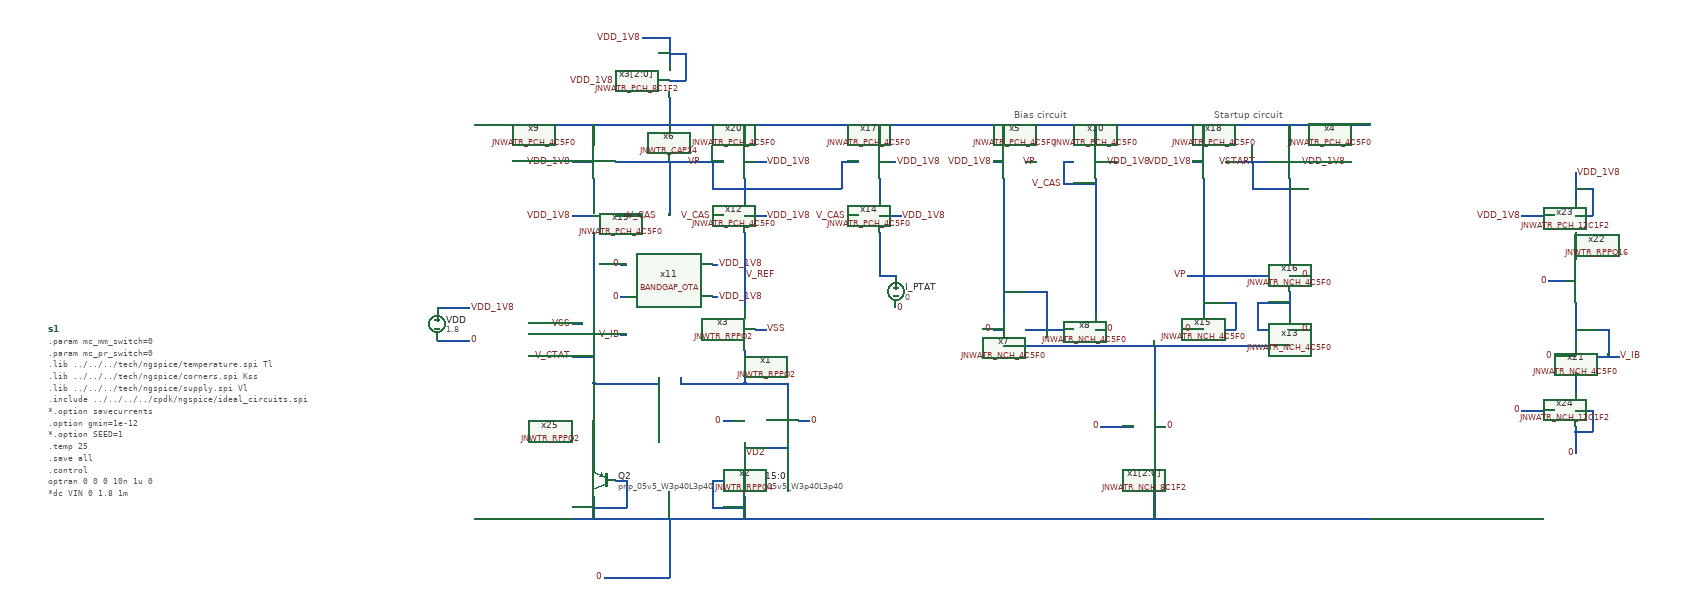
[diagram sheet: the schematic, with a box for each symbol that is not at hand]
v {xschem version=3.4.7 file_version=1.2}
G {}
K {}
V {}
S {}
E {}
B 2 -1480 -430 -680 -30 {flags=graph
y1=-2.0070292e-10
y2=1.6056831e-10
ypos1=0
ypos2=2
divy=5
subdivy=1
unity=1
x1=-0.00047041005
x2=0.0022870997
divx=5
subdivx=1
xlabmag=1.0
ylabmag=1.0
dataset=-1
unitx=1
logx=0
logy=0
hilight_wave=0
color=4
node=i(vdd)}
T {Startup circuit} 970 -230 0 0 0.4 0.4 {}
T {Bias circuit} 600 -230 0 0 0.4 0.4 {}
N -140 -130 60 -130 {lab=VP}
N -60 270 -60 280 {lab=V_CTAT}
N -180 280 -60 280 {lab=V_CTAT}
N -20 270 -20 280 {lab=DV}
N 100 390 100 430 {lab=VD2}
N -180 280 -180 430 {lab=V_CTAT}
N 40 510 100 510 {lab=0}
N 40 460 40 510 {lab=0}
N 40 460 60 460 {lab=0}
N 350 -130 380 -130 {lab=VDD_1V8}
N 280 -130 310 -130 {lab=VP}
N 350 0 350 80 {lab=#net1}
N -130 120 -120 120 {lab=0}
N 40 120 50 120 {lab=VDD_1V8}
N 100 -130 140 -130 {lab=VDD_1V8}
N -220 -130 -180 -130 {lab=VDD_1V8}
N -180 -200 -180 -160 {lab=#net2}
N 100 -200 100 -160 {lab=#net2}
N 350 -200 350 -160 {lab=#net2}
N 350 80 380 80 {lab=#net1}
N -220 230 -180 230 {lab=V_CTAT}
N 40 -130 40 -80 {lab=VP}
N 280 -130 280 -80 {lab=VP}
N -40 -130 -40 -30 {lab=VP}
N -40 -250 -40 -200 {lab=#net2}
N -140 -280 -80 -280 {lab=VDD_1V8}
N -40 -360 -40 -310 {lab=VDD_1V8}
N -90 -360 -40 -360 {lab=VDD_1V8}
N 40 60 50 60 {lab=VDD_1V8}
N -40 -280 -10 -280 {lab=VDD_1V8}
N -10 -330 -10 -280 {lab=VDD_1V8}
N -40 -330 -10 -330 {lab=VDD_1V8}
N -130 60 -120 60 {lab=0}
N -130 190 -120 190 {lab=V_IB}
N 580 -80 580 -60 {lab=#net3}
N 580 -100 580 -80 {lab=#net3}
N 580 -200 580 -160 {lab=#net2}
N -220 -30 -180 -30 {lab=VDD_1V8}
N -140 -30 -120 -30 {lab=V_CAS}
N -180 -100 -180 -60 {lab=#net4}
N 100 -100 100 -60 {lab=#net5}
N 100 -30 140 -30 {lab=VDD_1V8}
N 40 -30 60 -30 {lab=V_CAS}
N 350 -30 390 -30 {lab=VDD_1V8}
N 350 -100 350 -60 {lab=#net6}
N 290 -30 310 -30 {lab=V_CAS}
N 580 -60 580 -10 {lab=#net3}
N 580 -10 580 150 {lab=#net3}
N -180 510 -120 510 {lab=0}
N -120 460 -120 510 {lab=0}
N -140 460 -120 460 {lab=0}
N 620 180 640 180 {lab=#net3}
N 640 180 710 180 {lab=#net3}
N 620 -130 640 -130 {lab=VP}
N 690 -130 710 -130 {lab=V_CAS}
N 690 -130 690 -90 {lab=V_CAS}
N 690 -90 750 -90 {lab=V_CAS}
N 750 -100 750 150 {lab=V_CAS}
N 750 -200 750 -160 {lab=#net2}
N 580 110 660 110 {lab=#net3}
N 660 110 660 180 {lab=#net3}
N -180 490 -180 530 {lab=0}
N 100 490 100 530 {lab=0}
N 40 -80 280 -80 {lab=VP}
N -400 530 290 530 {lab=0}
N 1110 -200 1110 -160 {lab=#net2}
N -400 -200 1150 -200 {lab=#net2}
N 950 -200 950 -160 {lab=#net2}
N 1150 -200 1260 -200 {lab=#net2}
N 750 -130 770 -130 {lab=VDD_1V8}
N 930 -130 950 -130 {lab=VDD_1V8}
N 1110 -130 1130 -130 {lab=VDD_1V8}
N 560 -130 580 -130 {lab=VDD_1V8}
N 750 180 770 180 {lab=0}
N 560 180 580 180 {lab=0}
N 1110 80 1130 80 {lab=0}
N 990 -130 1070 -130 {lab=VSTART}
N 1040 -130 1040 -80 {lab=VSTART}
N 1040 -80 1110 -80 {lab=VSTART}
N 1050 180 1070 180 {lab=#net7}
N 1110 180 1130 180 {lab=0}
N 1050 130 1050 180 {lab=#net7}
N 1110 110 1110 150 {lab=#net7}
N 1050 130 1110 130 {lab=#net7}
N 990 180 1010 180 {lab=VP}
N 930 180 950 180 {lab=0}
N 1010 130 1010 180 {lab=VP}
N 950 130 1010 130 {lab=VP}
N 950 -100 950 150 {lab=VP}
N 950 80 1070 80 {lab=VP}
N 1110 -100 1110 50 {lab=VSTART}
N 920 80 950 80 {lab=VP}
N -20 280 100 280 {lab=DV}
N 100 280 180 280 {lab=DV}
N 180 280 180 310 {lab=DV}
N 180 390 180 400 {lab=VD2}
N 100 400 180 400 {lab=VD2}
N 200 350 220 350 {lab=0}
N 60 350 80 350 {lab=0}
N -140 -280 -80 -280 {lab=VDD_1V8}
N 290 530 1260 530 {lab=0}
N -160 640 -40 640 {lab=0}
N 760 360 820 360 {lab=0}
N -40 530 -40 640 {lab=0}
N 860 360 880 360 {lab=0}
N 860 390 860 530 {lab=0}
N 580 210 1110 210 {lab=#net8}
N 860 210 860 330 {lab=#net8}
N 1680 230 1720 230 {lab=V_IB}
N 1700 180 1700 230 {lab=V_IB}
N 1640 180 1700 180 {lab=V_IB}
N 1600 230 1640 230 {lab=0}
N 1640 370 1640 410 {lab=0}
N 1590 90 1620 90 {lab=0}
N 1540 -30 1600 -30 {lab=VDD_1V8}
N 1640 -110 1640 -60 {lab=VDD_1V8}
N 1640 -30 1670 -30 {lab=VDD_1V8}
N 1670 -80 1670 -30 {lab=VDD_1V8}
N 1640 -80 1670 -80 {lab=VDD_1V8}
N 1640 360 1640 370 {lab=0}
N 1540 330 1600 330 {lab=0}
N 1640 330 1670 330 {lab=0}
N 1670 330 1670 370 {lab=0}
N 1640 370 1670 370 {lab=0}
N 1640 260 1640 300 {lab=#net9}
N 1640 130 1640 200 {lab=V_IB}
N -470 140 -410 140 {lab=VDD_1V8}
N -470 200 -410 200 {lab=0}
N 1640 -0 1640 50 {lab=#net10}
N 120 180 140 180 {lab=VSS}
N 100 -0 100 140 {lab=V_REF}
N 100 220 100 280 {lab=DV}
N -220 170 -200 170 {lab=VSS}
N -180 -0 -180 130 {lab=#net11}
N -180 210 -180 280 {lab=V_CTAT}
C {devices/lab_wire.sym} -130 120 0 0 {name=p9 sig_type=std_logic lab=0}
C {devices/lab_pin.sym} 100 410 0 1 {name=p13 sig_type=std_logic lab=VD2}
C {devices/lab_pin.sym} 100 240 0 1 {name=p18 sig_type=std_logic lab=DV}
C {devices/lab_wire.sym} 20 -130 0 0 {name=p3 sig_type=std_logic lab=VP}
C {sky130_fd_pr/pnp_05v5.sym} 80 460 0 0 {name=Q2[15:0]
model=pnp_05v5_W3p40L3p40
m=1
spiceprefix=X
}
C {devices/lab_wire.sym} 50 120 0 1 {name=p6 sig_type=std_logic lab=VDD_1V8}
C {devices/lab_wire.sym} -220 -130 0 0 {name=p21 sig_type=std_logic lab=VDD_1V8}
C {devices/lab_wire.sym} 140 -130 0 1 {name=p22 sig_type=std_logic lab=VDD_1V8}
C {devices/lab_wire.sym} 380 -130 0 1 {name=p23 sig_type=std_logic lab=VDD_1V8}
C {JNW_ATR_SKY130A/JNWATR_PCH_4C5F0.sym} 60 -130 0 0 {name=x20}
C {JNW_ATR_SKY130A/JNWATR_PCH_4C5F0.sym} -140 -130 0 1 {name=x9}
C {JNW_ATR_SKY130A/JNWATR_PCH_4C5F0.sym} 310 -130 0 0 {name=x17}
C {devices/title.sym} -310 -420 0 0 {name=l1 author="Martin Solvik, Kim Hamberg, Henrik Alstadhaug"}
C {devices/lab_wire.sym} -130 190 0 0 {name=p10 sig_type=std_logic lab=V_IB}
C {JNW_ATR_SKY130A/JNWATR_PCH_4C5F0.sym} 620 -130 0 1 {name=x5}
C {devices/lab_wire.sym} 560 -130 0 0 {name=p14 sig_type=std_logic lab=VDD_1V8}
C {JNW_ATR_SKY130A/JNWATR_PCH_4C5F0.sym} -140 -30 0 1 {name=x19}
C {devices/lab_wire.sym} -220 -30 0 0 {name=p27 sig_type=std_logic lab=VDD_1V8}
C {devices/lab_wire.sym} -120 -30 0 1 {name=p28 sig_type=std_logic lab=V_CAS}
C {LELO_GR03_SKY130A/BANDGAP_OTA.sym} -20 120 1 1 {name=x11}
C {JNW_ATR_SKY130A/JNWATR_PCH_4C5F0.sym} 60 -30 0 0 {name=x12}
C {devices/lab_wire.sym} 140 -30 0 1 {name=p31 sig_type=std_logic lab=VDD_1V8}
C {devices/lab_wire.sym} 40 -30 0 0 {name=p32 sig_type=std_logic lab=V_CAS}
C {JNW_ATR_SKY130A/JNWATR_PCH_4C5F0.sym} 310 -30 0 0 {name=x14}
C {devices/lab_wire.sym} 390 -30 0 1 {name=p34 sig_type=std_logic lab=VDD_1V8}
C {sky130_fd_pr/pnp_05v5.sym} -160 460 0 1 {name=Q2
model=pnp_05v5_W3p40L3p40
m=1
spiceprefix=X
}
C {JNW_ATR_SKY130A/JNWATR_NCH_4C5F0.sym} 620 180 0 1 {name=x7}
C {devices/lab_wire.sym} 560 180 2 1 {name=p25 sig_type=std_logic lab=0}
C {JNW_ATR_SKY130A/JNWATR_NCH_4C5F0.sym} 710 180 0 0 {name=x8}
C {devices/lab_wire.sym} 770 180 2 0 {name=p29 sig_type=std_logic lab=0}
C {JNW_ATR_SKY130A/JNWATR_PCH_4C5F0.sym} 710 -130 0 0 {name=x10}
C {devices/lab_wire.sym} 690 -90 3 0 {name=p33 sig_type=std_logic lab=V_CAS}
C {devices/lab_wire.sym} 770 -130 0 1 {name=p35 sig_type=std_logic lab=VDD_1V8}
C {devices/lab_wire.sym} 640 -130 1 1 {name=p24 sig_type=std_logic lab=VP}
C {JNW_ATR_SKY130A/JNWATR_PCH_8C1F2.sym} -80 -280 0 0 {name=x3[2:0]}
C {JNW_ATR_SKY130A/JNWATR_NCH_4C5F0.sym} 1070 80 0 0 {name=x16}
C {JNW_ATR_SKY130A/JNWATR_PCH_4C5F0.sym} 990 -130 0 1 {name=x18}
C {devices/lab_wire.sym} 930 -130 0 0 {name=p40 sig_type=std_logic lab=VDD_1V8}
C {devices/lab_wire.sym} 1130 -130 0 1 {name=p42 sig_type=std_logic lab=VDD_1V8}
C {devices/lab_wire.sym} 1130 80 2 0 {name=p43 sig_type=std_logic lab=0}
C {JNW_ATR_SKY130A/JNWATR_PCH_4C5F0.sym} 1070 -130 0 0 {name=x4}
C {JNW_ATR_SKY130A/JNWATR_NCH_4C5F0.sym} 1070 180 0 0 {name=x13}
C {devices/lab_wire.sym} 1130 180 2 0 {name=p11 sig_type=std_logic lab=0}
C {JNW_ATR_SKY130A/JNWATR_NCH_4C5F0.sym} 990 180 0 1 {name=x15}
C {devices/lab_wire.sym} 930 180 2 1 {name=p37 sig_type=std_logic lab=0}
C {devices/lab_wire.sym} 920 80 0 0 {name=p39 sig_type=std_logic lab=VP}
C {JNW_TR_SKY130A/JNWTR_CAPX4.sym} -40 -140 0 0 {name=x6 }
C {devices/lab_wire.sym} 290 -30 0 0 {name=p46 sig_type=std_logic lab=V_CAS}
C {devices/lab_pin.sym} 220 350 0 1 {name=p36 sig_type=std_logic lab=0}
C {JNW_TR_SKY130A/JNWTR_RPPO4.sym} 180 390 3 0 {name=x2 }
C {devices/lab_pin.sym} 60 350 0 0 {name=p5 sig_type=std_logic lab=0}
C {JNW_TR_SKY130A/JNWTR_RPPO2.sym} 100 310 1 0 {name=x1 }
C {devices/lab_wire.sym} 1050 -130 0 0 {name=p51 sig_type=std_logic lab=VSTART}
C {JNW_ATR_SKY130A/JNWATR_NCH_8C1F2.sym} 820 360 0 0 {name=x1[2:0]}
C {devices/lab_wire.sym} 880 360 2 0 {name=p19 sig_type=std_logic lab=0}
C {devices/code_shown.sym} -1190 180 0 0 {name=s1 only_toplevel=false value="
.param mc_mm_switch=0
.param mc_pr_switch=0

.lib "../../../tech/ngspice/temperature.spi" Tl
.lib "../../../tech/ngspice/corners.spi" Kss
.lib "../../../tech/ngspice/supply.spi" Vl
.include ../../../../cpdk/ngspice/ideal_circuits.spi
*.option savecurrents
.option gmin=1e-12
*.option SEED=1
.temp 25
.save all
.control

optran 0 0 0 10n 1u 0
*dc VIN 0 1.8 1m
tran 0.5u 6m
*op
*ac dec 20 1 1G

write BANDGAP_CIRCUIT_TB_xsch.raw

exit
.endc
"}
C {devices/lab_wire.sym} -160 640 2 1 {name=p2 sig_type=std_logic lab=0}
C {devices/lab_wire.sym} 1720 230 0 1 {name=p7 sig_type=std_logic lab=V_IB}
C {devices/lab_wire.sym} 1590 90 2 1 {name=p53 sig_type=std_logic lab=0}
C {JNW_ATR_SKY130A/JNWATR_NCH_4C5F0.sym} 1680 230 0 1 {name=x21}
C {JNW_TR_SKY130A/JNWTR_RPPO16.sym} 1640 50 1 0 {name=x22 }
C {devices/lab_wire.sym} 1600 230 2 1 {name=p54 sig_type=std_logic lab=0}
C {devices/lab_pin.sym} 1640 410 0 0 {name=l29 sig_type=std_logic lab=0}
C {devices/lab_pin.sym} 1640 -110 0 1 {name=l31 sig_type=std_logic lab=VDD_1V8}
C {JNW_ATR_SKY130A/JNWATR_PCH_12C1F2.sym} 1600 -30 0 0 {name=x23}
C {JNW_ATR_SKY130A/JNWATR_NCH_12C1F2.sym} 1600 330 0 0 {name=x24}
C {devices/lab_wire.sym} -90 -360 0 0 {name=p1 sig_type=std_logic lab=VDD_1V8}
C {devices/lab_wire.sym} -410 140 0 1 {name=p57 sig_type=std_logic lab=VDD_1V8}
C {devices/lab_wire.sym} -410 200 2 0 {name=p58 sig_type=std_logic lab=0}
C {devices/lab_wire.sym} -220 230 0 0 {name=p8 sig_type=std_logic lab=V_CTAT}
C {devices/vsource.sym} 380 110 0 0 {name=I_PTAT
value=0
savecurrent=false
}
C {devices/lab_wire.sym} 380 140 2 0 {name=p4 sig_type=std_logic lab=0}
C {devices/lab_wire.sym} 760 360 2 1 {name=p12 sig_type=std_logic lab=0}
C {devices/vsource.sym} -470 170 0 0 {name=VDD
value=1.8
savecurrent=false}
C {devices/lab_wire.sym} -130 60 0 0 {name=p15 sig_type=std_logic lab=0}
C {devices/lab_wire.sym} 50 60 0 1 {name=p16 sig_type=std_logic lab=VDD_1V8}
C {devices/lab_wire.sym} -140 -280 0 0 {name=p17 sig_type=std_logic lab=VDD_1V8}
C {devices/lab_wire.sym} 1540 330 2 1 {name=p20 sig_type=std_logic lab=0}
C {devices/lab_wire.sym} 1540 -30 0 0 {name=p26 sig_type=std_logic lab=VDD_1V8}
C {devices/lab_pin.sym} 140 180 2 0 {name=p30 sig_type=std_logic lab=VSS}
C {JNW_TR_SKY130A/JNWTR_RPPO2.sym} 100 220 3 0 {name=x3 }
C {devices/lab_pin.sym} -220 170 2 1 {name=p38 sig_type=std_logic lab=VSS}
C {JNW_TR_SKY130A/JNWTR_RPPO2.sym} -180 210 1 1 {name=x25 }
C {devices/lab_pin.sym} 100 80 0 1 {name=p41 sig_type=std_logic lab=V_REF}
